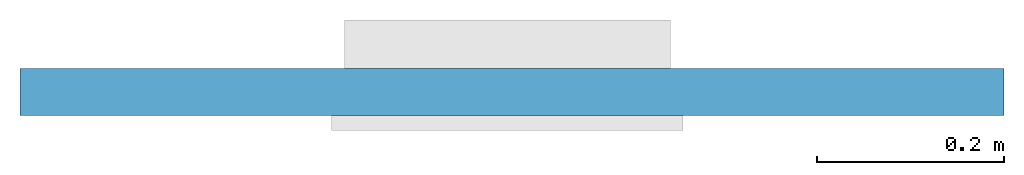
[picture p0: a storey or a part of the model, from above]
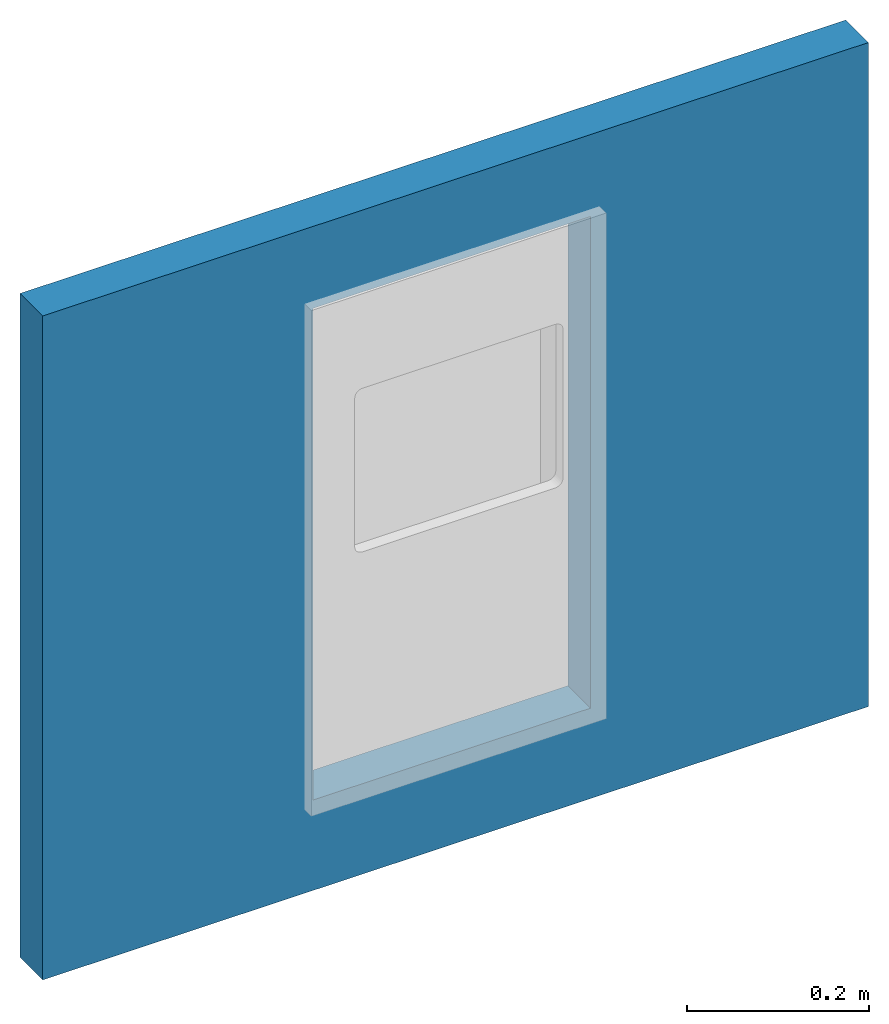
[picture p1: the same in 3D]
Properties of the parts of a building model (IFC2X3)

# File
Description: ViewDefinition [CoordinationView]
Time: 2019-01-16T09:03:35
Written by: The EXPRESS Data Manager Version 5.01.0100.02.64mod : 6 Jun 2012
Made in: 20140709_2115(x64) - Exporter 2014.0.2014.0709 - Default UI
Comment: STEP Physical File produced by: The EXPRESS Data Manager Version 5.01.0100.02.64mod : 6 Jun 2012 * Module: EDMstepFileFactory/EDMstandAlone * Creation date: Wed Jan 16 09:03:35 2019 * Host: BIM-HP * Database: C:\Users\dcole\AppData\Local\Temp\{17443C3F-190D-4764-9D1D-5019DC890640}\ifc * Database version: 5507 * Database creation date: Wed Jan 16 09:03:33 2019 * Schema: IFC2X3 * Model: DataRepository.ifc * Model creation date: Wed Jan 16 09:03:34 2019 * Header model: DataRepository.ifc_HeaderModel * Header model creation date: Wed Jan 16 09:03:34 2019 * EDMuser: sdai-user * EDMgroup: sdai-group * License ID and type: 5605 : Permanent license. Expiry date: * EDMstepFileFactory options: 020000

# IfcProject
LongName: P:\Fastrack\53721_DOLPHIN SOLUTIONS LIMITED\ADDITIONAL DRAWINGS 2019 BIM\IFC\09-3000.ifc

# IfcSite, Default
RefLatitude: 42, 24, 53, 508911; RefLongitude: -71, -15, -29, -58837; RefElevation: 0 mm

# IfcBuilding
Pset_BuildingCommon - NumberOfStoreys: 1

# IfcBuildingStorey, Level 1
LongName: Level 1; Elevation: 0 mm
Constraints - Elevation Base: Project Base Point; Elevation: 0 mm
Graphics - Color: 0; Line Weight: 1; Symbol at End 2 Default: yes; Line Pattern: -3000010; Symbol at End 1 Default: no
Identity Data - Structural: no; Building Story: yes; Name: Level 1
Dimensions - Computation Height: 0 mm

# IfcBuildingElementProxy: 09.3000 Dolphin 2 in 1 Combination Unit - Bespoke Finish, 09-3000:09.3000 Dolphin 2 in 1 Combination Unit - Bespoke Finish:122379
In: Level 1
Material: Stainless Steel
Dimensions - Volume: 0.00437643 m3; Recess: 360W x 665H x 110D; Projection: 16mm; Capacity Paper Towels: 100 'C' fold or 150 interleave paper towels; Height: 680mm; Width: 375mm
Constraints - Host: Level : Level 1; Level: Level: Level 1; Moves With Nearby Elements: no; Offset: -158.08 mm
Phasing - Phase Created: New Construction
Pset_ManufacturerTypeInformation - Manufacturer: Dolphin Solutions Limited
Pset_BuildingElementProxyCommon - Reference: 09.3000 Dolphin 2 in 1 Combination Unit - Bespoke Finish
General - Product Page Link: http://www.dolphinsolutions.co.uk/en/product/dolphin-2-1-combination-unit-bespoke-finish; Product Data: 2 in 1 Recessed satin stainless steel combination paper towel and waste bin unit. Capicity - 100 'C' fold or 150 interleave paper towels. Removable 8 litre stainless steel waste paper bin. Usage: Low Traffic Area. Satin stainless steel finish. Available with glass, acrylic or corian fascias.; Usage: Low Traffic Area; Capacity Bin: 8 Litres
Identity Data - Description: 2 in 1 combination unit - bespoke finish; Tel No.: +44 (0) 1424 202224; Assembly Code: D2090900; Model: 09.3000; Address: Southpoint, Compass Park, Bodiam, Robertsbridge, TN32 5BS; Fax No.: +44 (0) 1424 205200; Email: info@dolphinsolutions.co.uk; URL: www.dolphinsolutions.co.uk; Manufacturer: Dolphin Solutions Limited; Assembly Description: Misc. Other Plumbing Systems
Materials and Finishes - Finish: Satin stainless steel.; Fascia: Glass, Acrylic or Corian finish

# IfcOpeningElement: Opening (2)
In: Level 1
Phasing - Phase Created: New Construction
Name | Volume (m3)
 | 0.0351962 | Constraints - Unconnected Height: 892.67 mm; Base Extension Distance: 0 mm; Location Line: Finish Face: Interior; Related to Mass: no; Room Bounding: yes; Top Offset: 0 mm; Top Extension Distance: 0 mm; Base is Attached: no; Base Constraint: Level: Level 1; Base Offset: 95.7468 mm; Top is Attached: no; Structural - Enable Analytical Model: no; Structural: no; Structural Usage: Non-bearing; Dimensions - Length: 1050 mm; Area: 0.703924 m2; Construction - Function: Exterior; Wrapping at Inserts: Do not wrap; Width: 50 mm; Analytical Properties - Roughness: 1; Absorptance: 0.1; Graphics - Coarse Scale Fill Color: 8454143
09-3000:09.3000 Dolphin 2 in 1 Combination Unit - Bespoke Finish:122379:1 | 0.00437643 | Constraints - Host: Level : Level 1; Level: Level: Level 1; Moves With Nearby Elements: no; Offset: -158.08 mm; Pset_ManufacturerTypeInformation - Manufacturer: Dolphin Solutions Limited; General - Product Page Link: http://www.dolphinsolutions.co.uk/en/product/dolphin-2-1-combination-unit-bespoke-finish; Product Data: 2 in 1 Recessed satin stainless steel combination paper towel and waste bin unit. Capicity - 100 'C' fold or 150 interleave paper towels. Removable 8 litre stainless steel waste paper bin. Usage: Low Traffic Area. Satin stainless steel finish. Available with glass, acrylic or corian fascias.; Usage: Low Traffic Area; Capacity Bin: 8 Litres; Identity Data - Description: 2 in 1 combination unit - bespoke finish; Tel No.: +44 (0) 1424 202224; Assembly Code: D2090900; Model: 09.3000; Address: Southpoint, Compass Park, Bodiam, Robertsbridge, TN32 5BS; Fax No.: +44 (0) 1424 205200; Email: info@dolphinsolutions.co.uk; URL: www.dolphinsolutions.co.uk; Manufacturer: Dolphin Solutions Limited; Assembly Description: Misc. Other Plumbing Systems; Dimensions - Recess: 360W x 665H x 110D; Projection: 16mm; Capacity Paper Towels: 100 'C' fold or 150 interleave paper towels; Height: 680mm; Width: 375mm; Materials and Finishes - Finish: Satin stainless steel.; Fascia: Glass, Acrylic or Corian finish

# IfcWallStandardCase: Basic Wall:Wall 1, Basic Wall:Wall 1:3092
In: Level 1
Type - PredefinedType: STANDARD; Material: Default Wall 50 mm
Type - Construction - Function: Exterior; Wrapping at Inserts: Do not wrap; Width: 50 mm
Type - Analytical Properties - Roughness: 1; Absorptance: 0.1
Type - Graphics - Coarse Scale Fill Color: 8454143
Constraints - Unconnected Height: 892.67 mm; Base Extension Distance: 0 mm; Location Line: Finish Face: Interior; Related to Mass: no; Room Bounding: yes; Top Offset: 0 mm; Top Extension Distance: 0 mm; Base is Attached: no; Base Constraint: Level: Level 1; Base Offset: 95.7468 mm; Top is Attached: no
Phasing - Phase Created: New Construction
Structural - Enable Analytical Model: no; Structural: no; Structural Usage: Non-bearing
Dimensions - Volume: 0.0351962 m3; Length: 1050 mm; Area: 0.703924 m2
Pset_WallCommon - Reference: Wall 1; LoadBearing: no; ExtendToStructure: no; IsExternal: yes
